One B-rep face of a CAD part: STEP entity #40698.
In plain terms, the planar face has unit normal (0, 0, 1).
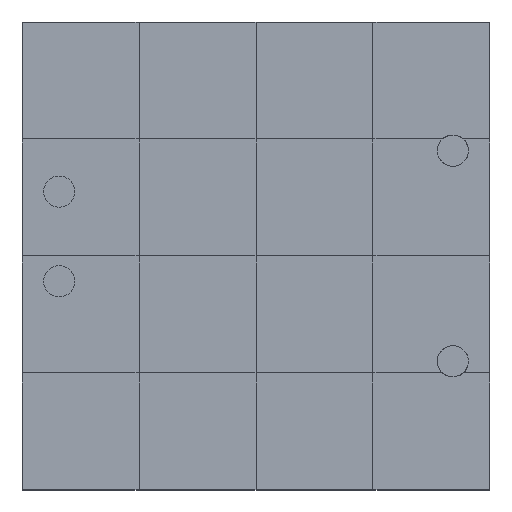
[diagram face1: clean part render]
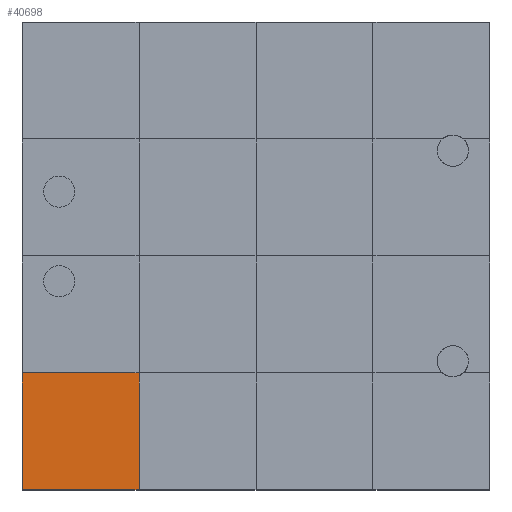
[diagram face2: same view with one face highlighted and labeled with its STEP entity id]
Its self-contained STEP definition (entity closure, numbers rounded to 3 decimals):
#40509 = VERTEX_POINT('',#40510);
#40510 = CARTESIAN_POINT('',(0.,0.,1.5));
#40517 = PLANE('',#40518);
#40518 = AXIS2_PLACEMENT_3D('',#40519,#40520,#40521);
#40519 = CARTESIAN_POINT('',(0.,0.,0.));
#40520 = DIRECTION('',(1.,0.,-0.));
#40521 = DIRECTION('',(0.,0.,1.));
#40529 = PLANE('',#40530);
#40530 = AXIS2_PLACEMENT_3D('',#40531,#40532,#40533);
#40531 = CARTESIAN_POINT('',(0.,0.,0.));
#40532 = DIRECTION('',(-0.,1.,0.));
#40533 = DIRECTION('',(0.,0.,1.));
#40570 = VERTEX_POINT('',#40571);
#40571 = CARTESIAN_POINT('',(0.,3.,1.5));
#40597 = EDGE_CURVE('',#40509,#40570,#40598,.T.);
#40598 = SURFACE_CURVE('',#40599,(#40603,#40610),.PCURVE_S1.);
#40599 = LINE('',#40600,#40601);
#40600 = CARTESIAN_POINT('',(0.,0.,1.5));
#40601 = VECTOR('',#40602,1.);
#40602 = DIRECTION('',(-0.,1.,0.));
#40603 = PCURVE('',#40517,#40604);
#40604 = DEFINITIONAL_REPRESENTATION('',(#40605),#40609);
#40605 = LINE('',#40606,#40607);
#40606 = CARTESIAN_POINT('',(1.5,0.));
#40607 = VECTOR('',#40608,1.);
#40608 = DIRECTION('',(0.,-1.));
#40609 = ( GEOMETRIC_REPRESENTATION_CONTEXT(2) 
PARAMETRIC_REPRESENTATION_CONTEXT() REPRESENTATION_CONTEXT('2D SPACE',''
  ) );
#40610 = PCURVE('',#40611,#40616);
#40611 = PLANE('',#40612);
#40612 = AXIS2_PLACEMENT_3D('',#40613,#40614,#40615);
#40613 = CARTESIAN_POINT('',(0.,0.,1.5));
#40614 = DIRECTION('',(0.,0.,1.));
#40615 = DIRECTION('',(1.,0.,-0.));
#40616 = DEFINITIONAL_REPRESENTATION('',(#40617),#40621);
#40617 = LINE('',#40618,#40619);
#40618 = CARTESIAN_POINT('',(0.,0.));
#40619 = VECTOR('',#40620,1.);
#40620 = DIRECTION('',(0.,1.));
#40621 = ( GEOMETRIC_REPRESENTATION_CONTEXT(2) 
PARAMETRIC_REPRESENTATION_CONTEXT() REPRESENTATION_CONTEXT('2D SPACE',''
  ) );
#40650 = EDGE_CURVE('',#40509,#40651,#40653,.T.);
#40651 = VERTEX_POINT('',#40652);
#40652 = CARTESIAN_POINT('',(3.,0.,1.5));
#40653 = SURFACE_CURVE('',#40654,(#40658,#40665),.PCURVE_S1.);
#40654 = LINE('',#40655,#40656);
#40655 = CARTESIAN_POINT('',(0.,0.,1.5));
#40656 = VECTOR('',#40657,1.);
#40657 = DIRECTION('',(1.,0.,-0.));
#40658 = PCURVE('',#40529,#40659);
#40659 = DEFINITIONAL_REPRESENTATION('',(#40660),#40664);
#40660 = LINE('',#40661,#40662);
#40661 = CARTESIAN_POINT('',(1.5,0.));
#40662 = VECTOR('',#40663,1.);
#40663 = DIRECTION('',(0.,1.));
#40664 = ( GEOMETRIC_REPRESENTATION_CONTEXT(2) 
PARAMETRIC_REPRESENTATION_CONTEXT() REPRESENTATION_CONTEXT('2D SPACE',''
  ) );
#40665 = PCURVE('',#40611,#40666);
#40666 = DEFINITIONAL_REPRESENTATION('',(#40667),#40671);
#40667 = LINE('',#40668,#40669);
#40668 = CARTESIAN_POINT('',(0.,0.));
#40669 = VECTOR('',#40670,1.);
#40670 = DIRECTION('',(1.,0.));
#40671 = ( GEOMETRIC_REPRESENTATION_CONTEXT(2) 
PARAMETRIC_REPRESENTATION_CONTEXT() REPRESENTATION_CONTEXT('2D SPACE',''
  ) );
#40698 = ADVANCED_FACE('',(#40699),#40611,.T.);
#40699 = FACE_BOUND('',#40700,.T.);
#40700 = EDGE_LOOP('',(#40701,#40702,#40703,#40731));
#40701 = ORIENTED_EDGE('',*,*,#40597,.F.);
#40702 = ORIENTED_EDGE('',*,*,#40650,.T.);
#40703 = ORIENTED_EDGE('',*,*,#40704,.T.);
#40704 = EDGE_CURVE('',#40651,#40705,#40707,.T.);
#40705 = VERTEX_POINT('',#40706);
#40706 = CARTESIAN_POINT('',(3.,3.,1.5));
#40707 = SURFACE_CURVE('',#40708,(#40712,#40719),.PCURVE_S1.);
#40708 = LINE('',#40709,#40710);
#40709 = CARTESIAN_POINT('',(3.,0.,1.5));
#40710 = VECTOR('',#40711,1.);
#40711 = DIRECTION('',(-0.,1.,0.));
#40712 = PCURVE('',#40611,#40713);
#40713 = DEFINITIONAL_REPRESENTATION('',(#40714),#40718);
#40714 = LINE('',#40715,#40716);
#40715 = CARTESIAN_POINT('',(3.,0.));
#40716 = VECTOR('',#40717,1.);
#40717 = DIRECTION('',(0.,1.));
#40718 = ( GEOMETRIC_REPRESENTATION_CONTEXT(2) 
PARAMETRIC_REPRESENTATION_CONTEXT() REPRESENTATION_CONTEXT('2D SPACE',''
  ) );
#40719 = PCURVE('',#40720,#40725);
#40720 = PLANE('',#40721);
#40721 = AXIS2_PLACEMENT_3D('',#40722,#40723,#40724);
#40722 = CARTESIAN_POINT('',(3.,0.,1.5));
#40723 = DIRECTION('',(0.,0.,1.));
#40724 = DIRECTION('',(1.,0.,-0.));
#40725 = DEFINITIONAL_REPRESENTATION('',(#40726),#40730);
#40726 = LINE('',#40727,#40728);
#40727 = CARTESIAN_POINT('',(0.,0.));
#40728 = VECTOR('',#40729,1.);
#40729 = DIRECTION('',(0.,1.));
#40730 = ( GEOMETRIC_REPRESENTATION_CONTEXT(2) 
PARAMETRIC_REPRESENTATION_CONTEXT() REPRESENTATION_CONTEXT('2D SPACE',''
  ) );
#40731 = ORIENTED_EDGE('',*,*,#40732,.F.);
#40732 = EDGE_CURVE('',#40570,#40705,#40733,.T.);
#40733 = SURFACE_CURVE('',#40734,(#40738,#40745),.PCURVE_S1.);
#40734 = LINE('',#40735,#40736);
#40735 = CARTESIAN_POINT('',(0.,3.,1.5));
#40736 = VECTOR('',#40737,1.);
#40737 = DIRECTION('',(1.,0.,-0.));
#40738 = PCURVE('',#40611,#40739);
#40739 = DEFINITIONAL_REPRESENTATION('',(#40740),#40744);
#40740 = LINE('',#40741,#40742);
#40741 = CARTESIAN_POINT('',(0.,3.));
#40742 = VECTOR('',#40743,1.);
#40743 = DIRECTION('',(1.,0.));
#40744 = ( GEOMETRIC_REPRESENTATION_CONTEXT(2) 
PARAMETRIC_REPRESENTATION_CONTEXT() REPRESENTATION_CONTEXT('2D SPACE',''
  ) );
#40745 = PCURVE('',#40746,#40751);
#40746 = PLANE('',#40747);
#40747 = AXIS2_PLACEMENT_3D('',#40748,#40749,#40750);
#40748 = CARTESIAN_POINT('',(0.,3.,1.5));
#40749 = DIRECTION('',(0.,0.,1.));
#40750 = DIRECTION('',(1.,0.,-0.));
#40751 = DEFINITIONAL_REPRESENTATION('',(#40752),#40756);
#40752 = LINE('',#40753,#40754);
#40753 = CARTESIAN_POINT('',(0.,0.));
#40754 = VECTOR('',#40755,1.);
#40755 = DIRECTION('',(1.,0.));
#40756 = ( GEOMETRIC_REPRESENTATION_CONTEXT(2) 
PARAMETRIC_REPRESENTATION_CONTEXT() REPRESENTATION_CONTEXT('2D SPACE',''
  ) );
